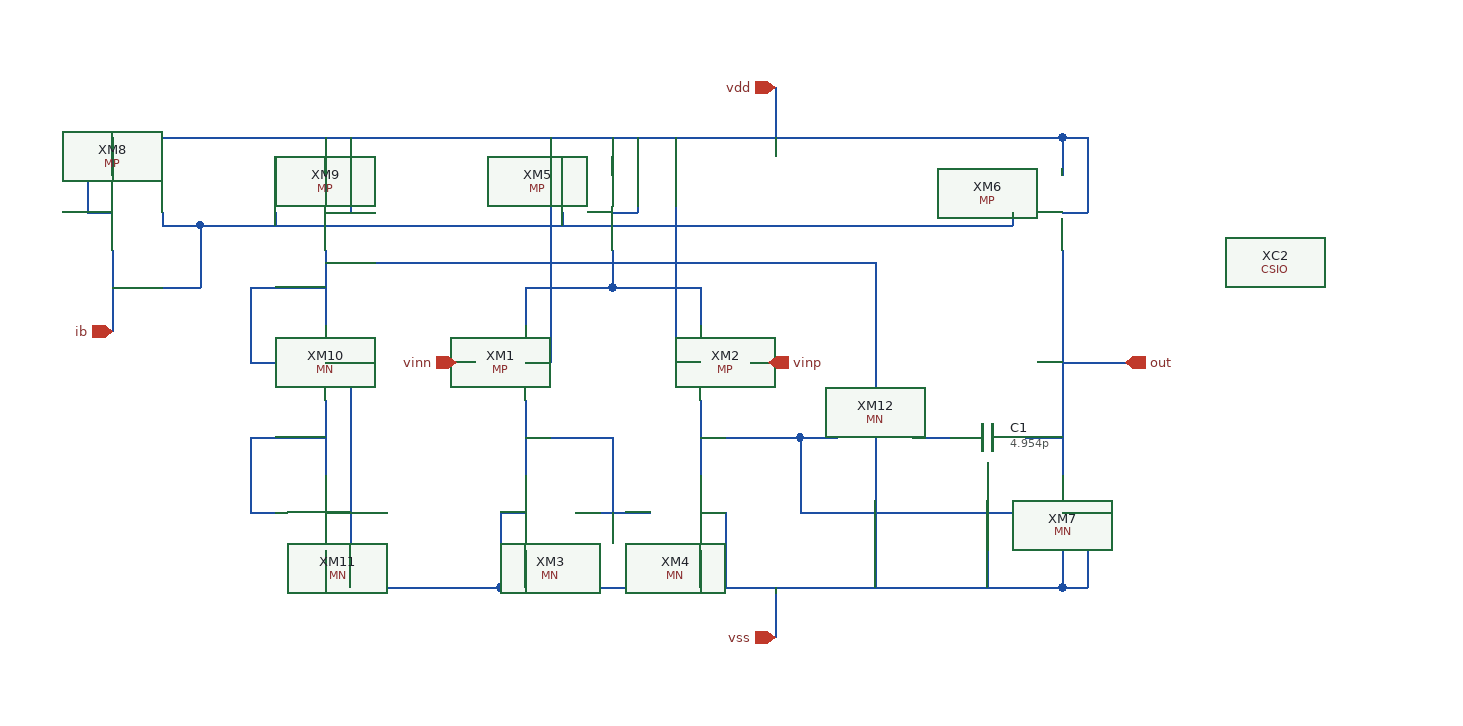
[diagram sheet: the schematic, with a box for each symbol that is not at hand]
v {xschem version=3.4.8RC file_version=1.3}
G {}
K {}
V {}
S {}
F {}
E {}
N 0 -60 70 -60 {lab=#net1}
N 70 -60 140 -60 {lab=#net1}
N -0 30 -0 90 {lab=#net2}
N 40 120 100 120 {lab=#net2}
N 140 30 140 90 {lab=#net3}
N 0 60 70 60 {lab=#net2}
N 70 60 70 120 {lab=#net2}
N -0 150 0 180 {lab=vss}
N 140 150 140 180 {lab=vss}
N 0 -60 0 -30 {lab=#net1}
N 140 -60 140 -30 {lab=#net1}
N 70 -90 70 -60 {lab=#net1}
N 70 -180 70 -150 {lab=vdd}
N 430 -180 430 -150 {lab=vdd}
N 430 150 430 180 {lab=vss}
N 430 -90 430 90 {lab=out}
N 220 120 310 120 {lab=#net3}
N 220 60 250 60 {lab=#net3}
N -330 -180 -330 -150 {lab=vdd}
N -290 -110 -260 -110 {lab=ib}
N 70 -120 90 -120 {lab=vdd}
N 90 -180 90 -120 {lab=vdd}
N 390 -120 390 -110 {lab=ib}
N 0 -110 310 -110 {lab=ib}
N 430 -120 450 -120 {lab=vdd}
N 450 -180 450 -120 {lab=vdd}
N 430 -180 450 -180 {lab=vdd}
N -350 -120 -330 -120 {lab=vdd}
N -350 -180 -350 -120 {lab=vdd}
N -330 -90 -330 -25 {lab=ib}
N -330 -60 -260 -60 {lab=ib}
N 30 -120 30 -110 {lab=ib}
N -120 -110 0 -110 {lab=ib}
N -20 120 0 120 {lab=vss}
N -20 120 -20 180 {lab=vss}
N 140 120 160 120 {lab=vss}
N 160 120 160 180 {lab=vss}
N 430 120 450 120 {lab=vss}
N 450 120 450 180 {lab=vss}
N 430 180 450 180 {lab=vss}
N 140 60 220 60 {lab=#net3}
N 220 60 220 120 {lab=#net3}
N -55 0 -40 0 {lab=vinn}
N 180 0 195 0 {lab=vinp}
N 0 0 20 0 {lab=vdd}
N 20 -180 20 0 {lab=vdd}
N 125 0 140 -0 {lab=vdd}
N 120 0 125 0 {lab=vdd}
N 120 -180 120 0 {lab=vdd}
N -290 -120 -290 -110 {lab=ib}
N -260 -110 -260 -60 {lab=ib}
N 430 0 480 0 {lab=out}
N -210 -180 350 -180 {lab=vdd}
N -20 180 350 180 {lab=vss}
N -160 180 -20 180 {lab=vss}
N -160 30 -160 90 {lab=#net4}
N -160 150 -160 180 {lab=vss}
N -220 120 -200 120 {lab=#net4}
N -220 60 -160 60 {lab=#net4}
N -220 -0 -200 -0 {lab=#net5}
N -220 -60 -160 -60 {lab=#net5}
N -160 -90 -160 -30 {lab=#net5}
N -160 120 -140 120 {lab=vss}
N -160 0 -140 -0 {lab=vss}
N -140 0 -140 180 {lab=vss}
N -350 -180 -210 -180 {lab=vdd}
N -260 -110 -120 -110 {lab=ib}
N -160 -120 -140 -120 {lab=vdd}
N -140 -180 -140 -120 {lab=vdd}
N -160 -180 -160 -150 {lab=vdd}
N -200 -120 -200 -110 {lab=ib}
N -220 -60 -220 -0 {lab=#net5}
N -220 60 -220 120 {lab=#net4}
N 280 60 280 180 {lab=vss}
N 310 120 390 120 {lab=#net3}
N 350 180 430 180 {lab=vss}
N 310 60 340 60 {lab=#net6}
N 310 -110 390 -110 {lab=ib}
N 350 -180 430 -180 {lab=vdd}
N 280 -70 280 20 {lab=#net5}
N -160 -80 280 -80 {lab=#net5}
N 280 -80 280 -70 {lab=#net5}
N 400 60 430 60 {lab=out}
N 370 80 370 180 {lab=vss}
N 200 -220 200 -180 {lab=vdd}
N 200 180 200 220 {lab=vss}
C {TR-1umLIB/MP.sym} -40 0 0 0 {name=XM1
model=PMOS
w=300u
l=5u
m=1
spiceprefix=X
as=0
ad=0
ps=0
pd=0
nrd=0
nrs=0}
C {TR-1umLIB/MN.sym} 100 120 0 0 {name=XM4
model=NMOS
w=200u
l=5u
m=1
spiceprefix=X
as=0
ad=0
ps=0
pd=0
nrd=0
nrs=0}
C {TR-1umLIB/MP.sym} 180 0 0 1 {name=XM2
model=PMOS
w=300u
l=5u
m=1
spiceprefix=X
as=0
ad=0
ps=0
pd=0
nrd=0
nrs=0}
C {TR-1umLIB/MN.sym} 40 120 0 1 {name=XM3
model=NMOS
w=200u
l=5u
m=1
spiceprefix=X
as=0
ad=0
ps=0
pd=0
nrd=0
nrs=0}
C {TR-1umLIB/MP.sym} 30 -120 0 0 {name=XM5
model=PMOS
w=400u
l=5u
m=1
spiceprefix=X
as=0
ad=0
ps=0
pd=0
nrd=0
nrs=0}
C {TR-1umLIB/MP.sym} 390 -120 0 0 {name=XM6
model=PMOS
w=800u
l=5u
m=1
spiceprefix=X
as=0
ad=0
ps=0
pd=0
nrd=0
nrs=0}
C {TR-1umLIB/MN.sym} 390 120 0 0 {name=XM7
model=NMOS
w=800u
l=5u
m=1
spiceprefix=X
as=0
ad=0
ps=0
pd=0
nrd=0
nrs=0}
C {TR-1umLIB/MP.sym} -290 -120 0 1 {name=XM8
model=PMOS
w=25u
l=5u
m=1
spiceprefix=X
as=0
ad=0
ps=0
pd=0
nrd=0
nrs=0}
C {devices/ipin.sym} -55 0 0 0 {name=p2 lab=vinn}
C {devices/ipin.sym} 195 0 0 1 {name=p6 lab=vinp}
C {devices/opin.sym} 480 0 0 0 {name=p4 lab=out}
C {devices/iopin.sym} -330 -25 1 0 {name=p8 lab=ib}
C {TR-1umLIB/MP.sym} -200 -120 0 0 {name=XM9
model=PMOS
w=50u
l=5u
m=1
spiceprefix=X
as=0
ad=0
ps=0
pd=0
nrd=0
nrs=0}
C {TR-1umLIB/MN.sym} -200 0 0 0 {name=XM10
model=NMOS
w=50u
l=5u
m=1
spiceprefix=X
as=0
ad=0
ps=0
pd=0
nrd=0
nrs=0}
C {TR-1umLIB/MN.sym} -200 120 0 0 {name=XM11
model=NMOS
w=50u
l=5u
m=1
spiceprefix=X
as=0
ad=0
ps=0
pd=0
nrd=0
nrs=0}
C {TR-1umLIB/MN.sym} 280 20 1 0 {name=XM12
model=NMOS
w=100u
l=5u
m=1
spiceprefix=X
as=0
ad=0
ps=0
pd=0
nrd=0
nrs=0}
C {devices/capa.sym} 370 60 3 0 {name=C1
m=4
value=4.954p
footprint=1206
device="ceramic capacitor"}
C {TR-1umLIB/CSIO.sym} 600 -80 0 0 {name=XC2
model=F_CSIO
spiceprefix=X
x=96u
y=86u
c="expr_eng( 0.6e-3 * @x * @y )"
a="expr_eng( @x * @y )"
p="expr_eng( 2 * ( @x + @y ) )"
m=4}
C {devices/iopin.sym} 200 -220 0 0 {name=p1 lab=vdd}
C {devices/iopin.sym} 200 220 0 0 {name=p3 lab=vss}
